VERSION 5.7 ;
  NOWIREEXTENSIONATPIN ON ;
  DIVIDERCHAR "/" ;
  BUSBITCHARS "[]" ;
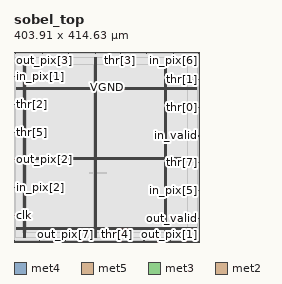
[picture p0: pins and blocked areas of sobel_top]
MACRO sobel_top
  CLASS BLOCK ;
  FOREIGN sobel_top ;
  ORIGIN 0.000 0.000 ;
  SIZE 403.910 BY 414.630 ;
  PIN VGND
    DIRECTION INOUT ;
    USE GROUND ;
    PORT
      LAYER met4 ;
        RECT 24.340 10.640 25.940 402.800 ;
    END
    PORT
      LAYER met4 ;
        RECT 177.940 10.640 179.540 402.800 ;
    END
    PORT
      LAYER met4 ;
        RECT 331.540 10.640 333.140 402.800 ;
    END
    PORT
      LAYER met5 ;
        RECT 5.280 30.030 398.600 31.630 ;
    END
    PORT
      LAYER met5 ;
        RECT 5.280 183.210 398.600 184.810 ;
    END
    PORT
      LAYER met5 ;
        RECT 5.280 336.390 398.600 337.990 ;
    END
  END VGND
  PIN VPWR
    DIRECTION INOUT ;
    USE POWER ;
    PORT
      LAYER met4 ;
        RECT 21.040 10.640 22.640 402.800 ;
    END
    PORT
      LAYER met4 ;
        RECT 174.640 10.640 176.240 402.800 ;
    END
    PORT
      LAYER met4 ;
        RECT 328.240 10.640 329.840 402.800 ;
    END
    PORT
      LAYER met5 ;
        RECT 5.280 26.730 398.600 28.330 ;
    END
    PORT
      LAYER met5 ;
        RECT 5.280 179.910 398.600 181.510 ;
    END
    PORT
      LAYER met5 ;
        RECT 5.280 333.090 398.600 334.690 ;
    END
  END VPWR
  PIN clk
    DIRECTION INPUT ;
    USE SIGNAL ;
    ANTENNAGATEAREA 0.852000 ;
    PORT
      LAYER met3 ;
        RECT 0.000 57.840 4.000 58.440 ;
    END
  END clk
  PIN in_pix[0]
    DIRECTION INPUT ;
    USE SIGNAL ;
    ANTENNAGATEAREA 0.159000 ;
    PORT
      LAYER met2 ;
        RECT 402.590 410.630 402.870 414.630 ;
    END
  END in_pix[0]
  PIN in_pix[1]
    DIRECTION INPUT ;
    USE SIGNAL ;
    ANTENNAGATEAREA 0.159000 ;
    PORT
      LAYER met3 ;
        RECT 0.000 360.440 4.000 361.040 ;
    END
  END in_pix[1]
  PIN in_pix[2]
    DIRECTION INPUT ;
    USE SIGNAL ;
    ANTENNAGATEAREA 0.126000 ;
    PORT
      LAYER met3 ;
        RECT 0.000 119.040 4.000 119.640 ;
    END
  END in_pix[2]
  PIN in_pix[3]
    DIRECTION INPUT ;
    USE SIGNAL ;
    ANTENNAGATEAREA 0.159000 ;
    PORT
      LAYER met2 ;
        RECT 119.230 410.630 119.510 414.630 ;
    END
  END in_pix[3]
  PIN in_pix[4]
    DIRECTION INPUT ;
    USE SIGNAL ;
    ANTENNAGATEAREA 0.159000 ;
    PORT
      LAYER met2 ;
        RECT 177.190 410.630 177.470 414.630 ;
    END
  END in_pix[4]
  PIN in_pix[5]
    DIRECTION INPUT ;
    USE SIGNAL ;
    ANTENNAGATEAREA 0.196500 ;
    PORT
      LAYER met3 ;
        RECT 399.910 112.240 403.910 112.840 ;
    END
  END in_pix[5]
  PIN in_pix[6]
    DIRECTION INPUT ;
    USE SIGNAL ;
    ANTENNAGATEAREA 0.159000 ;
    PORT
      LAYER met2 ;
        RECT 347.850 410.630 348.130 414.630 ;
    END
  END in_pix[6]
  PIN in_pix[7]
    DIRECTION INPUT ;
    USE SIGNAL ;
    ANTENNAGATEAREA 0.196500 ;
    PORT
      LAYER met2 ;
        RECT 283.450 0.000 283.730 4.000 ;
    END
  END in_pix[7]
  PIN in_valid
    DIRECTION INPUT ;
    USE SIGNAL ;
    ANTENNAGATEAREA 0.159000 ;
    PORT
      LAYER met3 ;
        RECT 399.910 231.240 403.910 231.840 ;
    END
  END in_valid
  PIN out_pix[0]
    DIRECTION OUTPUT TRISTATE ;
    USE SIGNAL ;
    ANTENNADIFFAREA 0.795200 ;
    PORT
      LAYER met2 ;
        RECT 289.890 410.630 290.170 414.630 ;
    END
  END out_pix[0]
  PIN out_pix[1]
    DIRECTION OUTPUT TRISTATE ;
    USE SIGNAL ;
    ANTENNADIFFAREA 0.795200 ;
    PORT
      LAYER met2 ;
        RECT 399.370 0.000 399.650 4.000 ;
    END
  END out_pix[1]
  PIN out_pix[2]
    DIRECTION OUTPUT TRISTATE ;
    USE SIGNAL ;
    ANTENNADIFFAREA 0.795200 ;
    PORT
      LAYER met3 ;
        RECT 0.000 180.240 4.000 180.840 ;
    END
  END out_pix[2]
  PIN out_pix[3]
    DIRECTION OUTPUT TRISTATE ;
    USE SIGNAL ;
    ANTENNADIFFAREA 0.795200 ;
    PORT
      LAYER met2 ;
        RECT 61.270 410.630 61.550 414.630 ;
    END
  END out_pix[3]
  PIN out_pix[4]
    DIRECTION OUTPUT TRISTATE ;
    USE SIGNAL ;
    ANTENNADIFFAREA 0.795200 ;
    PORT
      LAYER met2 ;
        RECT 341.410 0.000 341.690 4.000 ;
    END
  END out_pix[4]
  PIN out_pix[5]
    DIRECTION OUTPUT TRISTATE ;
    USE SIGNAL ;
    ANTENNADIFFAREA 0.795200 ;
    PORT
      LAYER met2 ;
        RECT 0.090 0.000 0.370 4.000 ;
    END
  END out_pix[5]
  PIN out_pix[6]
    DIRECTION OUTPUT TRISTATE ;
    USE SIGNAL ;
    ANTENNADIFFAREA 0.795200 ;
    PORT
      LAYER met2 ;
        RECT 54.830 0.000 55.110 4.000 ;
    END
  END out_pix[6]
  PIN out_pix[7]
    DIRECTION OUTPUT TRISTATE ;
    USE SIGNAL ;
    ANTENNADIFFAREA 0.795200 ;
    PORT
      LAYER met2 ;
        RECT 112.790 0.000 113.070 4.000 ;
    END
  END out_pix[7]
  PIN out_valid
    DIRECTION OUTPUT TRISTATE ;
    USE SIGNAL ;
    ANTENNADIFFAREA 0.445500 ;
    PORT
      LAYER met3 ;
        RECT 399.910 51.040 403.910 51.640 ;
    END
  END out_valid
  PIN reset
    DIRECTION INPUT ;
    USE SIGNAL ;
    ANTENNAGATEAREA 0.213000 ;
    PORT
      LAYER met2 ;
        RECT 170.750 0.000 171.030 4.000 ;
    END
  END reset
  PIN thr[0]
    DIRECTION INPUT ;
    USE SIGNAL ;
    ANTENNAGATEAREA 0.196500 ;
    PORT
      LAYER met3 ;
        RECT 399.910 292.440 403.910 293.040 ;
    END
  END thr[0]
  PIN thr[1]
    DIRECTION INPUT ;
    USE SIGNAL ;
    ANTENNAGATEAREA 0.213000 ;
    PORT
      LAYER met3 ;
        RECT 399.910 353.640 403.910 354.240 ;
    END
  END thr[1]
  PIN thr[2]
    DIRECTION INPUT ;
    USE SIGNAL ;
    ANTENNAGATEAREA 0.196500 ;
    PORT
      LAYER met3 ;
        RECT 0.000 299.240 4.000 299.840 ;
    END
  END thr[2]
  PIN thr[3]
    DIRECTION INPUT ;
    USE SIGNAL ;
    ANTENNAGATEAREA 0.159000 ;
    PORT
      LAYER met2 ;
        RECT 231.930 410.630 232.210 414.630 ;
    END
  END thr[3]
  PIN thr[4]
    DIRECTION INPUT ;
    USE SIGNAL ;
    ANTENNAGATEAREA 0.247500 ;
    PORT
      LAYER met2 ;
        RECT 225.490 0.000 225.770 4.000 ;
    END
  END thr[4]
  PIN thr[5]
    DIRECTION INPUT ;
    USE SIGNAL ;
    ANTENNAGATEAREA 0.126000 ;
    PORT
      LAYER met3 ;
        RECT 0.000 238.040 4.000 238.640 ;
    END
  END thr[5]
  PIN thr[6]
    DIRECTION INPUT ;
    USE SIGNAL ;
    ANTENNAGATEAREA 0.196500 ;
    PORT
      LAYER met2 ;
        RECT 3.310 410.630 3.590 414.630 ;
    END
  END thr[6]
  PIN thr[7]
    DIRECTION INPUT ;
    USE SIGNAL ;
    ANTENNAGATEAREA 0.247500 ;
    PORT
      LAYER met3 ;
        RECT 399.910 173.440 403.910 174.040 ;
    END
  END thr[7]
  OBS
      LAYER li1 ;
        RECT 5.520 10.795 398.360 402.645 ;
      LAYER met1 ;
        RECT 0.070 10.640 402.890 402.800 ;
      LAYER met2 ;
        RECT 0.100 410.350 3.030 411.130 ;
        RECT 3.870 410.350 60.990 411.130 ;
        RECT 61.830 410.350 118.950 411.130 ;
        RECT 119.790 410.350 176.910 411.130 ;
        RECT 177.750 410.350 231.650 411.130 ;
        RECT 232.490 410.350 289.610 411.130 ;
        RECT 290.450 410.350 347.570 411.130 ;
        RECT 348.410 410.350 402.310 411.130 ;
        RECT 0.100 4.280 402.860 410.350 ;
        RECT 0.650 4.000 54.550 4.280 ;
        RECT 55.390 4.000 112.510 4.280 ;
        RECT 113.350 4.000 170.470 4.280 ;
        RECT 171.310 4.000 225.210 4.280 ;
        RECT 226.050 4.000 283.170 4.280 ;
        RECT 284.010 4.000 341.130 4.280 ;
        RECT 341.970 4.000 399.090 4.280 ;
        RECT 399.930 4.000 402.860 4.280 ;
      LAYER met3 ;
        RECT 4.000 361.440 399.910 402.725 ;
        RECT 4.400 360.040 399.910 361.440 ;
        RECT 4.000 354.640 399.910 360.040 ;
        RECT 4.000 353.240 399.510 354.640 ;
        RECT 4.000 300.240 399.910 353.240 ;
        RECT 4.400 298.840 399.910 300.240 ;
        RECT 4.000 293.440 399.910 298.840 ;
        RECT 4.000 292.040 399.510 293.440 ;
        RECT 4.000 239.040 399.910 292.040 ;
        RECT 4.400 237.640 399.910 239.040 ;
        RECT 4.000 232.240 399.910 237.640 ;
        RECT 4.000 230.840 399.510 232.240 ;
        RECT 4.000 181.240 399.910 230.840 ;
        RECT 4.400 179.840 399.910 181.240 ;
        RECT 4.000 174.440 399.910 179.840 ;
        RECT 4.000 173.040 399.510 174.440 ;
        RECT 4.000 120.040 399.910 173.040 ;
        RECT 4.400 118.640 399.910 120.040 ;
        RECT 4.000 113.240 399.910 118.640 ;
        RECT 4.000 111.840 399.510 113.240 ;
        RECT 4.000 58.840 399.910 111.840 ;
        RECT 4.400 57.440 399.910 58.840 ;
        RECT 4.000 52.040 399.910 57.440 ;
        RECT 4.000 50.640 399.510 52.040 ;
        RECT 4.000 10.715 399.910 50.640 ;
      LAYER met4 ;
        RECT 19.615 19.895 20.640 386.745 ;
        RECT 23.040 19.895 23.940 386.745 ;
        RECT 26.340 19.895 174.240 386.745 ;
        RECT 176.640 19.895 177.540 386.745 ;
        RECT 179.940 19.895 327.840 386.745 ;
        RECT 330.240 19.895 331.140 386.745 ;
        RECT 333.540 19.895 379.665 386.745 ;
      LAYER met5 ;
        RECT 164.340 150.500 200.900 152.100 ;
  END
END sobel_top
END LIBRARY

